(* Logix 5000 project; controller CIP_Sync_Demo_AKD2G_Dual_Axes_v_2_1 vendor 1 type 14 code 156 rev 34.11; software revision 34.01; part 3 of 4 *)
(* tags used below, declared in another part *)
   StateMachineCurrentState : INT;
   UpdatePeriod : DINT;
   Unwind : DINT;
   AxisControlWord : INT;
   AxisVoltageEnabled : BOOL;
   AxisSwitchOnDisabled : BOOL;
   AxisRemote : BOOL;
   AxisHomeAttained : BOOL;
   AxisHomingError : BOOL;
   AxisMotionModeHoming : BOOL;
   AxisMotionModeCyclicPosition : BOOL;
   AxisFollowingError : BOOL;
   AxisStreamingActive : BOOL;
   UpdatePeriodMsgSent : BOOL;
   UnwindMsgSent : BOOL;
   IsRotary : SINT;
(* CIP_Axis_State_Machine, continued *)

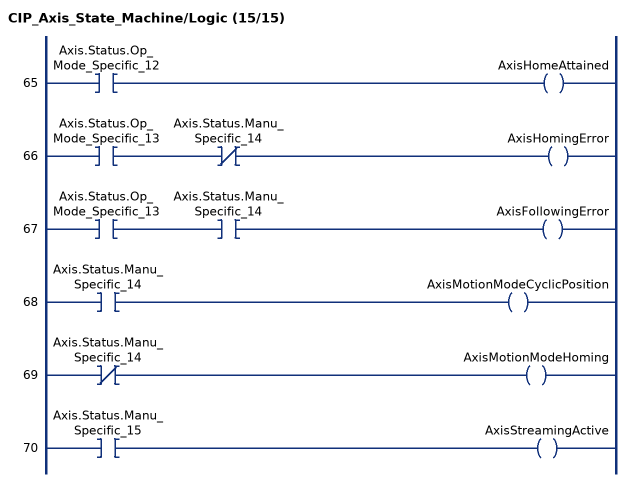
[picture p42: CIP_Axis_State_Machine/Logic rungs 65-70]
   65: XIC(Axis.Status.Op_Mode_Specific_12)OTE(AxisHomeAttained);
   66: XIC(Axis.Status.Op_Mode_Specific_13)XIO(Axis.Status.Manu_Specific_14)OTE(AxisHomingError);
   67: XIC(Axis.Status.Op_Mode_Specific_13)XIC(Axis.Status.Manu_Specific_14)OTE(AxisFollowingError);
   68: XIC(Axis.Status.Manu_Specific_14)OTE(AxisMotionModeCyclicPosition);
   69: XIO(Axis.Status.Manu_Specific_14)OTE(AxisMotionModeHoming);
   70: XIC(Axis.Status.Manu_Specific_15)OTE(AxisStreamingActive);
END_ROUTINE

ROUTINE Prescan   (* ladder *)
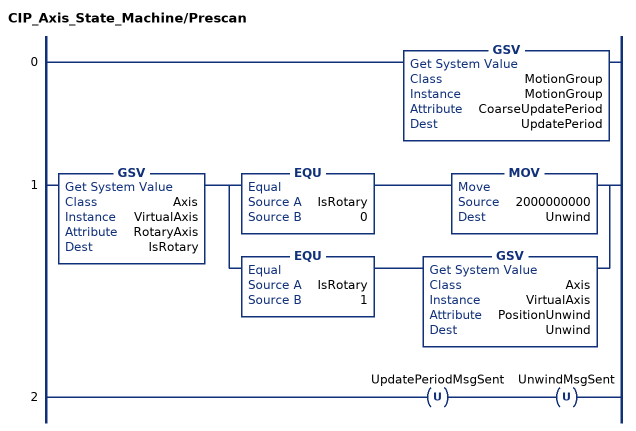
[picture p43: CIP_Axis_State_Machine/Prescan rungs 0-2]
   0: GSV(MotionGroup,MotionGroup,CoarseUpdatePeriod,UpdatePeriod);
   1: GSV(Axis,VirtualAxis,RotaryAxis,IsRotary)[EQU(IsRotary,0) MOV(2000000000,Unwind) ,EQU(IsRotary,1) GSV(Axis,VirtualAxis,PositionUnwind,Unwind) ];
   2: OTU(UpdatePeriodMsgSent)OTU(UnwindMsgSent);
END_ROUTINE
END_ADD_ON_INSTRUCTION

ADD_ON_INSTRUCTION CIP_Drive_Comms_Dual_Axis   (* revision 2.1, ExecutePrescan *)
// CIP Sync Drive Communications For AKD2G Dual Axis Drive
// Revision note:
// Changed local tag CycleStartTime from LINT to DINT[2]. Changed GSV destination and both COP instruction Source entries to use CycleStartTime[0] as a result of the change in data typing.
VAR_IN_OUT
   InputFromDrive : SINT[64]; {required}
   OutputToDrive : SINT[64]; {required}
   Axis1 : CIP_Axis; {required}
   Axis2 : CIP_Axis; {required}
   VirtualAxis1 : AXIS_VIRTUAL; {required}
   VirtualAxis2 : AXIS_VIRTUAL; {required}
   MotionGroup : MOTION_GROUP; {required}
   DynamicMap : CIP_DynamicMap; {required}
END_VAR
VAR
   CycleStartTime : DINT[2]; {access None}
   AxisPosition : DINT; {access None}
END_VAR

ROUTINE Logic   (* ladder *)
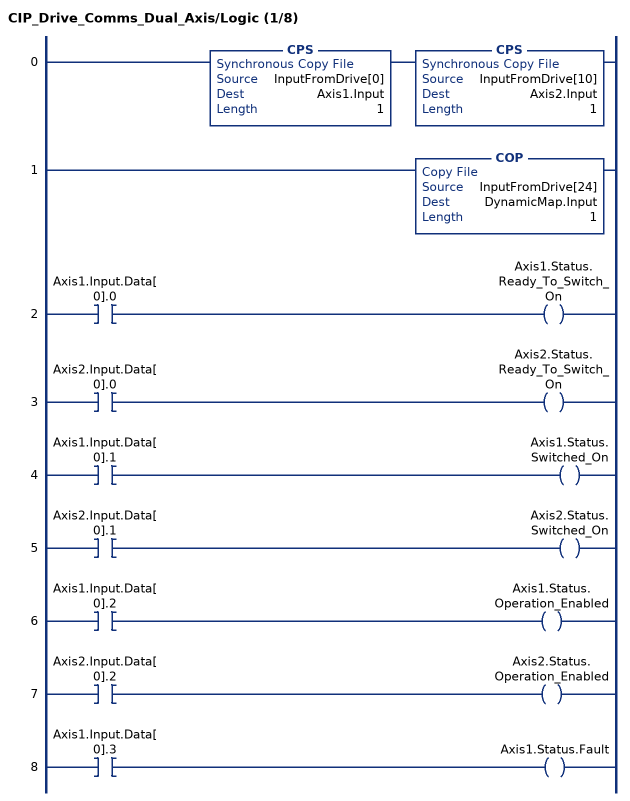
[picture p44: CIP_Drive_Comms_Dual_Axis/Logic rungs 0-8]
   0: CPS(InputFromDrive[0],Axis1.Input,1)CPS(InputFromDrive[10],Axis2.Input,1);
   1: COP(InputFromDrive[24],DynamicMap.Input,1);
   2: XIC(Axis1.Input.Data[0].0)OTE(Axis1.Status.Ready_To_Switch_On);
   3: XIC(Axis2.Input.Data[0].0)OTE(Axis2.Status.Ready_To_Switch_On);
   4: XIC(Axis1.Input.Data[0].1)OTE(Axis1.Status.Switched_On);
   5: XIC(Axis2.Input.Data[0].1)OTE(Axis2.Status.Switched_On);
   6: XIC(Axis1.Input.Data[0].2)OTE(Axis1.Status.Operation_Enabled);
   7: XIC(Axis2.Input.Data[0].2)OTE(Axis2.Status.Operation_Enabled);
   8: XIC(Axis1.Input.Data[0].3)OTE(Axis1.Status.Fault);
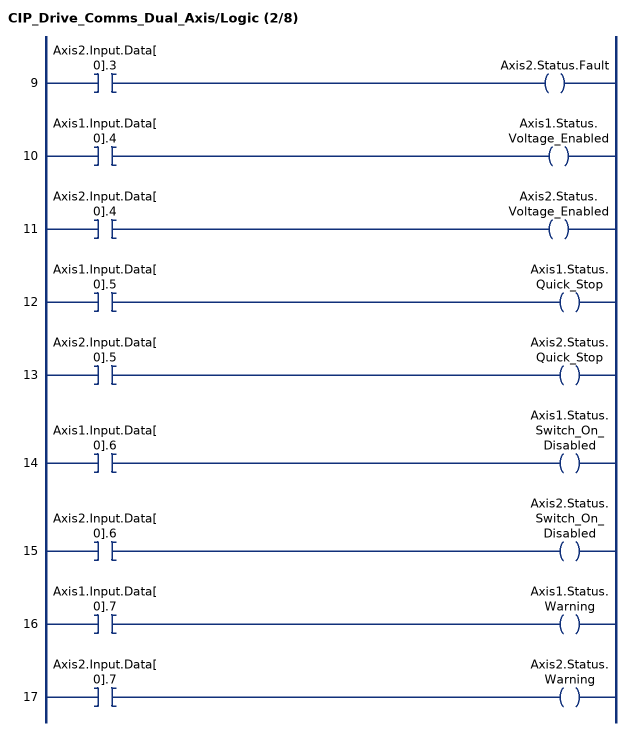
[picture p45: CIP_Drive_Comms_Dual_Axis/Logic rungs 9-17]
   9: XIC(Axis2.Input.Data[0].3)OTE(Axis2.Status.Fault);
   10: XIC(Axis1.Input.Data[0].4)OTE(Axis1.Status.Voltage_Enabled);
   11: XIC(Axis2.Input.Data[0].4)OTE(Axis2.Status.Voltage_Enabled);
   12: XIC(Axis1.Input.Data[0].5)OTE(Axis1.Status.Quick_Stop);
   13: XIC(Axis2.Input.Data[0].5)OTE(Axis2.Status.Quick_Stop);
   14: XIC(Axis1.Input.Data[0].6)OTE(Axis1.Status.Switch_On_Disabled);
   15: XIC(Axis2.Input.Data[0].6)OTE(Axis2.Status.Switch_On_Disabled);
   16: XIC(Axis1.Input.Data[0].7)OTE(Axis1.Status.Warning);
   17: XIC(Axis2.Input.Data[0].7)OTE(Axis2.Status.Warning);
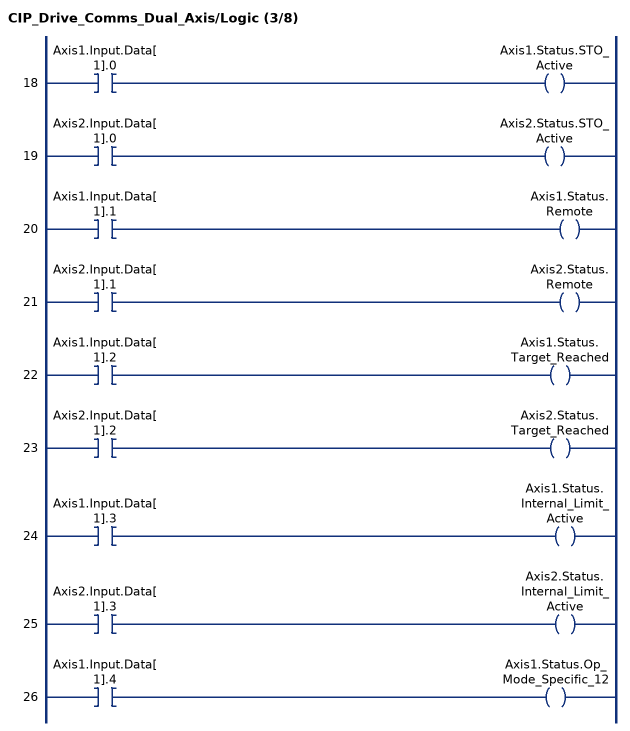
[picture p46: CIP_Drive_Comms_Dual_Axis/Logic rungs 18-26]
   18: XIC(Axis1.Input.Data[1].0)OTE(Axis1.Status.STO_Active);
   19: XIC(Axis2.Input.Data[1].0)OTE(Axis2.Status.STO_Active);
   20: XIC(Axis1.Input.Data[1].1)OTE(Axis1.Status.Remote);
   21: XIC(Axis2.Input.Data[1].1)OTE(Axis2.Status.Remote);
   22: XIC(Axis1.Input.Data[1].2)OTE(Axis1.Status.Target_Reached);
   23: XIC(Axis2.Input.Data[1].2)OTE(Axis2.Status.Target_Reached);
   24: XIC(Axis1.Input.Data[1].3)OTE(Axis1.Status.Internal_Limit_Active);
   25: XIC(Axis2.Input.Data[1].3)OTE(Axis2.Status.Internal_Limit_Active);
   26: XIC(Axis1.Input.Data[1].4)OTE(Axis1.Status.Op_Mode_Specific_12);
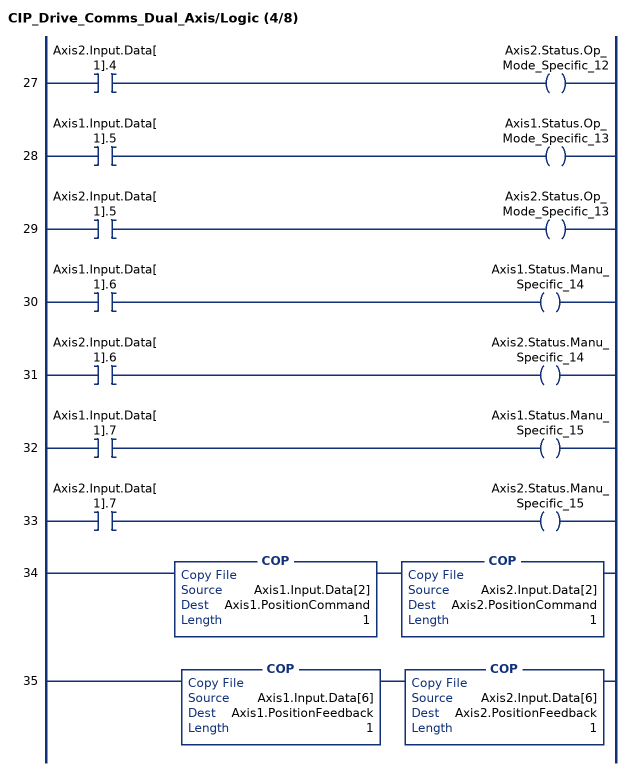
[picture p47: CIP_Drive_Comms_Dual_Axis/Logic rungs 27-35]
   27: XIC(Axis2.Input.Data[1].4)OTE(Axis2.Status.Op_Mode_Specific_12);
   28: XIC(Axis1.Input.Data[1].5)OTE(Axis1.Status.Op_Mode_Specific_13);
   29: XIC(Axis2.Input.Data[1].5)OTE(Axis2.Status.Op_Mode_Specific_13);
   30: XIC(Axis1.Input.Data[1].6)OTE(Axis1.Status.Manu_Specific_14);
   31: XIC(Axis2.Input.Data[1].6)OTE(Axis2.Status.Manu_Specific_14);
   32: XIC(Axis1.Input.Data[1].7)OTE(Axis1.Status.Manu_Specific_15);
   33: XIC(Axis2.Input.Data[1].7)OTE(Axis2.Status.Manu_Specific_15);
   34: COP(Axis1.Input.Data[2],Axis1.PositionCommand,1)COP(Axis2.Input.Data[2],Axis2.PositionCommand,1);
   35: COP(Axis1.Input.Data[6],Axis1.PositionFeedback,1)COP(Axis2.Input.Data[6],Axis2.PositionFeedback,1);
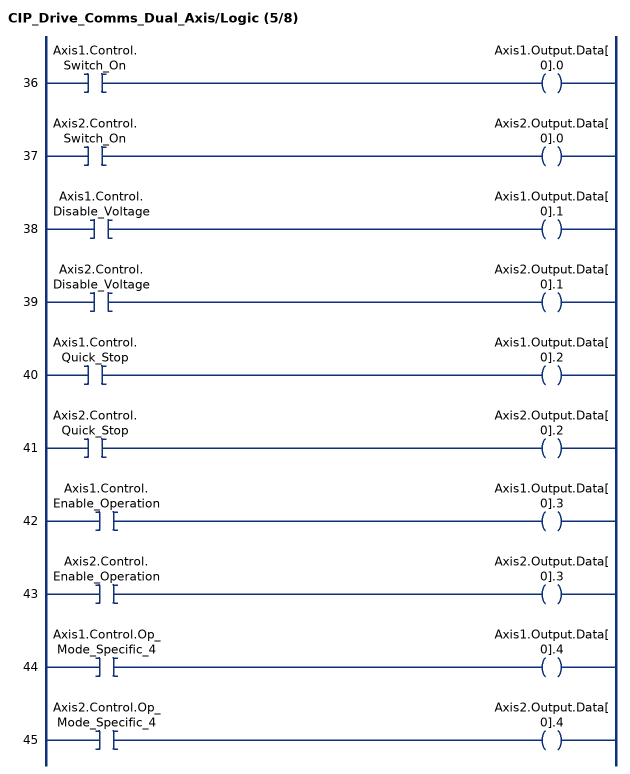
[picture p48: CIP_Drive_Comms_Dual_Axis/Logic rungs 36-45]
   36: XIC(Axis1.Control.Switch_On)OTE(Axis1.Output.Data[0].0);
   37: XIC(Axis2.Control.Switch_On)OTE(Axis2.Output.Data[0].0);
   38: XIC(Axis1.Control.Disable_Voltage)OTE(Axis1.Output.Data[0].1);
   39: XIC(Axis2.Control.Disable_Voltage)OTE(Axis2.Output.Data[0].1);
   40: XIC(Axis1.Control.Quick_Stop)OTE(Axis1.Output.Data[0].2);
   41: XIC(Axis2.Control.Quick_Stop)OTE(Axis2.Output.Data[0].2);
   42: XIC(Axis1.Control.Enable_Operation)OTE(Axis1.Output.Data[0].3);
   43: XIC(Axis2.Control.Enable_Operation)OTE(Axis2.Output.Data[0].3);
   44: XIC(Axis1.Control.Op_Mode_Specific_4)OTE(Axis1.Output.Data[0].4);
   45: XIC(Axis2.Control.Op_Mode_Specific_4)OTE(Axis2.Output.Data[0].4);
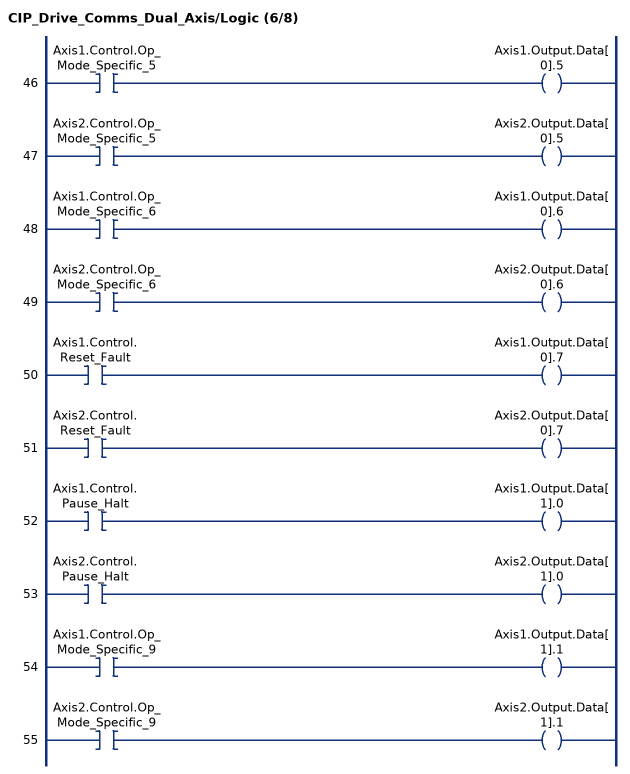
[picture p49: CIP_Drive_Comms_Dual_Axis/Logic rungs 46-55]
   46: XIC(Axis1.Control.Op_Mode_Specific_5)OTE(Axis1.Output.Data[0].5);
   47: XIC(Axis2.Control.Op_Mode_Specific_5)OTE(Axis2.Output.Data[0].5);
   48: XIC(Axis1.Control.Op_Mode_Specific_6)OTE(Axis1.Output.Data[0].6);
   49: XIC(Axis2.Control.Op_Mode_Specific_6)OTE(Axis2.Output.Data[0].6);
   50: XIC(Axis1.Control.Reset_Fault)OTE(Axis1.Output.Data[0].7);
   51: XIC(Axis2.Control.Reset_Fault)OTE(Axis2.Output.Data[0].7);
   52: XIC(Axis1.Control.Pause_Halt)OTE(Axis1.Output.Data[1].0);
   53: XIC(Axis2.Control.Pause_Halt)OTE(Axis2.Output.Data[1].0);
   54: XIC(Axis1.Control.Op_Mode_Specific_9)OTE(Axis1.Output.Data[1].1);
   55: XIC(Axis2.Control.Op_Mode_Specific_9)OTE(Axis2.Output.Data[1].1);
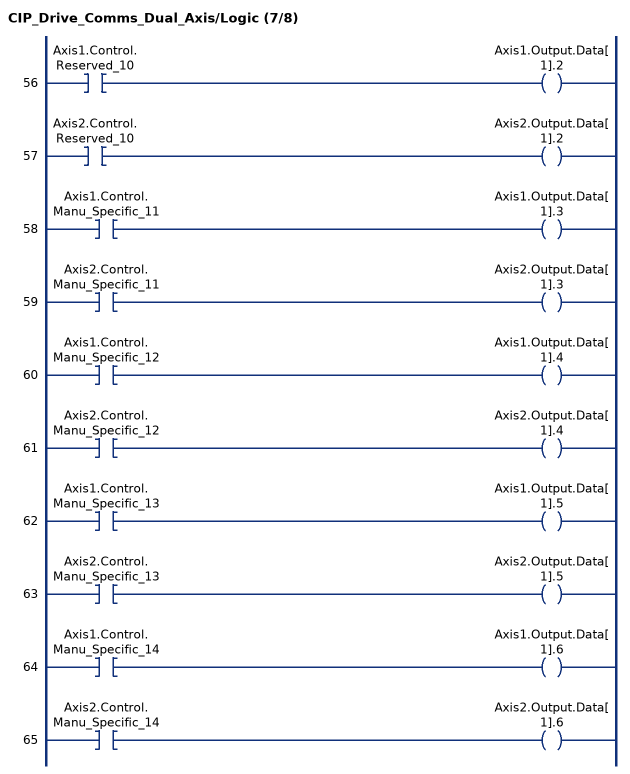
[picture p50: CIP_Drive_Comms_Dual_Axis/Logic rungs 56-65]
   56: XIC(Axis1.Control.Reserved_10)OTE(Axis1.Output.Data[1].2);
   57: XIC(Axis2.Control.Reserved_10)OTE(Axis2.Output.Data[1].2);
   58: XIC(Axis1.Control.Manu_Specific_11)OTE(Axis1.Output.Data[1].3);
   59: XIC(Axis2.Control.Manu_Specific_11)OTE(Axis2.Output.Data[1].3);
   60: XIC(Axis1.Control.Manu_Specific_12)OTE(Axis1.Output.Data[1].4);
   61: XIC(Axis2.Control.Manu_Specific_12)OTE(Axis2.Output.Data[1].4);
   62: XIC(Axis1.Control.Manu_Specific_13)OTE(Axis1.Output.Data[1].5);
   63: XIC(Axis2.Control.Manu_Specific_13)OTE(Axis2.Output.Data[1].5);
   64: XIC(Axis1.Control.Manu_Specific_14)OTE(Axis1.Output.Data[1].6);
   65: XIC(Axis2.Control.Manu_Specific_14)OTE(Axis2.Output.Data[1].6);
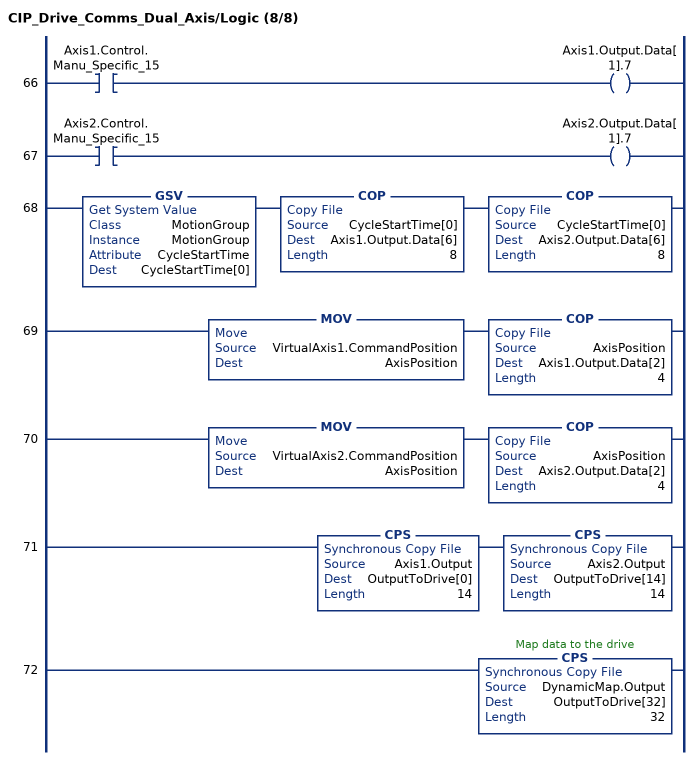
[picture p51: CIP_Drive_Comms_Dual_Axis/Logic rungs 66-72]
   66: XIC(Axis1.Control.Manu_Specific_15)OTE(Axis1.Output.Data[1].7);
   67: XIC(Axis2.Control.Manu_Specific_15)OTE(Axis2.Output.Data[1].7);
   68: GSV(MotionGroup,MotionGroup,CycleStartTime,CycleStartTime[0])COP(CycleStartTime[0],Axis1.Output.Data[6],8)COP(CycleStartTime[0],Axis2.Output.Data[6],8);
   69: MOV(VirtualAxis1.CommandPosition,AxisPosition)COP(AxisPosition,Axis1.Output.Data[2],4);
   70: MOV(VirtualAxis2.CommandPosition,AxisPosition)COP(AxisPosition,Axis2.Output.Data[2],4);
   71: CPS(Axis1.Output,OutputToDrive[0],14)CPS(Axis2.Output,OutputToDrive[14],14);
   72: CPS(DynamicMap.Output,OutputToDrive[32],32);
END_ROUTINE

ROUTINE Prescan   (* ladder *)
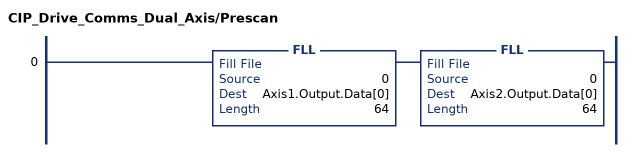
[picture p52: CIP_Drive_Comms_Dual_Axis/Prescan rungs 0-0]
   0: FLL(0,Axis1.Output.Data[0],64)FLL(0,Axis2.Output.Data[0],64);
END_ROUTINE
END_ADD_ON_INSTRUCTION

ADD_ON_INSTRUCTION CIP_Drive_Comms_Single_Axis   (* revision 2.1, ExecutePrescan *)
// CIP Sync Drive Communications For AKD2G Single Axis or Essentials Drive
// Revision note:
// Changed Local Tag CycleStartTime from LINT to DINT[2]
// Modified GSV Destination and COP Source to CycleStartTime[0] in rung 36 to accommodate the change in data typing.
VAR_IN_OUT
   InputFromDrive : SINT[64]; {required}
   OutputToDrive : SINT[64]; {required}
   Axis : CIP_Axis; {required}
   VirtualAxis : AXIS_VIRTUAL; {required}
   MotionGroup : MOTION_GROUP; {required}
   DynamicMap : CIP_DynamicMap; {required}
END_VAR
VAR
   CycleStartTime : DINT[2]; {access None}
   AxisPosition : DINT; {access None}
END_VAR

ROUTINE Logic   (* ladder *)
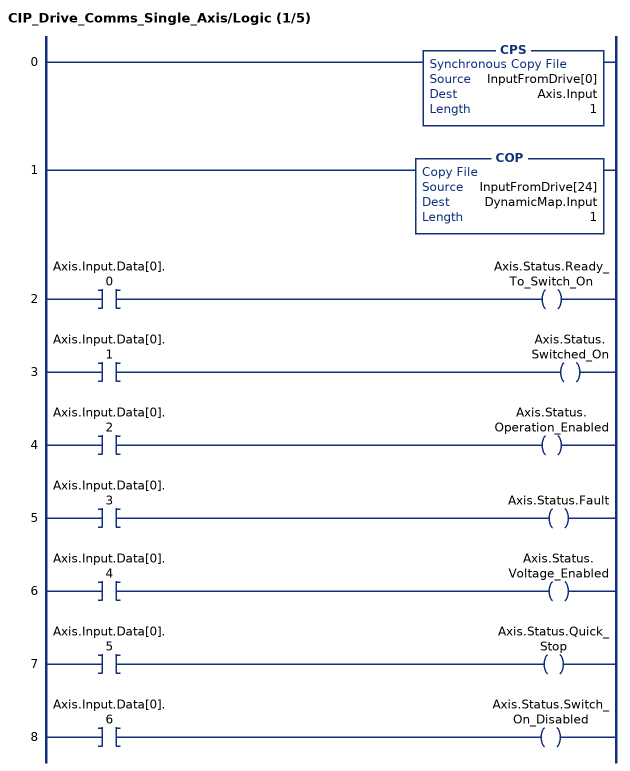
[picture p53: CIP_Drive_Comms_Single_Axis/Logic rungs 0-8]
   0: CPS(InputFromDrive[0],Axis.Input,1);
   1: COP(InputFromDrive[24],DynamicMap.Input,1);
   2: XIC(Axis.Input.Data[0].0)OTE(Axis.Status.Ready_To_Switch_On);
   3: XIC(Axis.Input.Data[0].1)OTE(Axis.Status.Switched_On);
   4: XIC(Axis.Input.Data[0].2)OTE(Axis.Status.Operation_Enabled);
   5: XIC(Axis.Input.Data[0].3)OTE(Axis.Status.Fault);
   6: XIC(Axis.Input.Data[0].4)OTE(Axis.Status.Voltage_Enabled);
   7: XIC(Axis.Input.Data[0].5)OTE(Axis.Status.Quick_Stop);
   8: XIC(Axis.Input.Data[0].6)OTE(Axis.Status.Switch_On_Disabled);
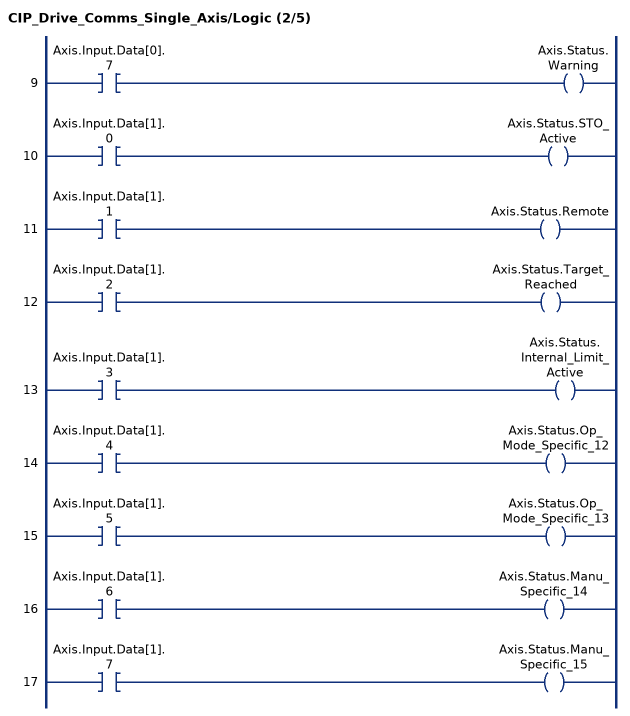
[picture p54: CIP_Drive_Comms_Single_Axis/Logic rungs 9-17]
   9: XIC(Axis.Input.Data[0].7)OTE(Axis.Status.Warning);
   10: XIC(Axis.Input.Data[1].0)OTE(Axis.Status.STO_Active);
   11: XIC(Axis.Input.Data[1].1)OTE(Axis.Status.Remote);
   12: XIC(Axis.Input.Data[1].2)OTE(Axis.Status.Target_Reached);
   13: XIC(Axis.Input.Data[1].3)OTE(Axis.Status.Internal_Limit_Active);
   14: XIC(Axis.Input.Data[1].4)OTE(Axis.Status.Op_Mode_Specific_12);
   15: XIC(Axis.Input.Data[1].5)OTE(Axis.Status.Op_Mode_Specific_13);
   16: XIC(Axis.Input.Data[1].6)OTE(Axis.Status.Manu_Specific_14);
   17: XIC(Axis.Input.Data[1].7)OTE(Axis.Status.Manu_Specific_15);
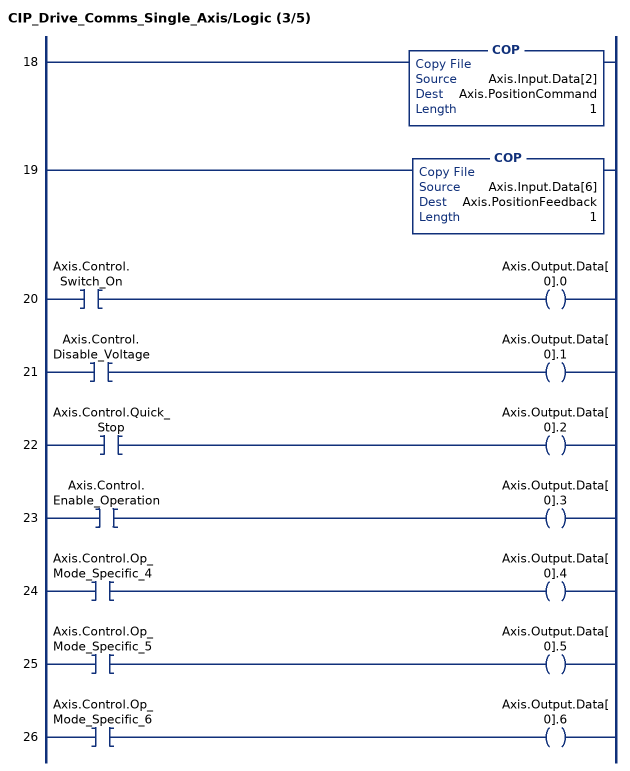
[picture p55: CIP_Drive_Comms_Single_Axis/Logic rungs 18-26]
   18: COP(Axis.Input.Data[2],Axis.PositionCommand,1);
   19: COP(Axis.Input.Data[6],Axis.PositionFeedback,1);
   20: XIC(Axis.Control.Switch_On)OTE(Axis.Output.Data[0].0);
   21: XIC(Axis.Control.Disable_Voltage)OTE(Axis.Output.Data[0].1);
   22: XIC(Axis.Control.Quick_Stop)OTE(Axis.Output.Data[0].2);
   23: XIC(Axis.Control.Enable_Operation)OTE(Axis.Output.Data[0].3);
   24: XIC(Axis.Control.Op_Mode_Specific_4)OTE(Axis.Output.Data[0].4);
   25: XIC(Axis.Control.Op_Mode_Specific_5)OTE(Axis.Output.Data[0].5);
   26: XIC(Axis.Control.Op_Mode_Specific_6)OTE(Axis.Output.Data[0].6);
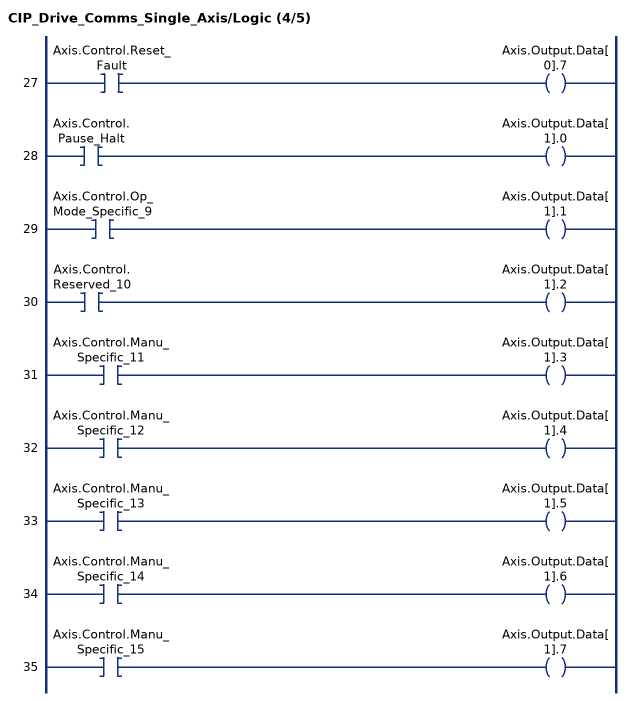
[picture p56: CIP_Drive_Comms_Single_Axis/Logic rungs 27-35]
   27: XIC(Axis.Control.Reset_Fault)OTE(Axis.Output.Data[0].7);
   28: XIC(Axis.Control.Pause_Halt)OTE(Axis.Output.Data[1].0);
   29: XIC(Axis.Control.Op_Mode_Specific_9)OTE(Axis.Output.Data[1].1);
   30: XIC(Axis.Control.Reserved_10)OTE(Axis.Output.Data[1].2);
   31: XIC(Axis.Control.Manu_Specific_11)OTE(Axis.Output.Data[1].3);
   32: XIC(Axis.Control.Manu_Specific_12)OTE(Axis.Output.Data[1].4);
   33: XIC(Axis.Control.Manu_Specific_13)OTE(Axis.Output.Data[1].5);
   34: XIC(Axis.Control.Manu_Specific_14)OTE(Axis.Output.Data[1].6);
   35: XIC(Axis.Control.Manu_Specific_15)OTE(Axis.Output.Data[1].7);
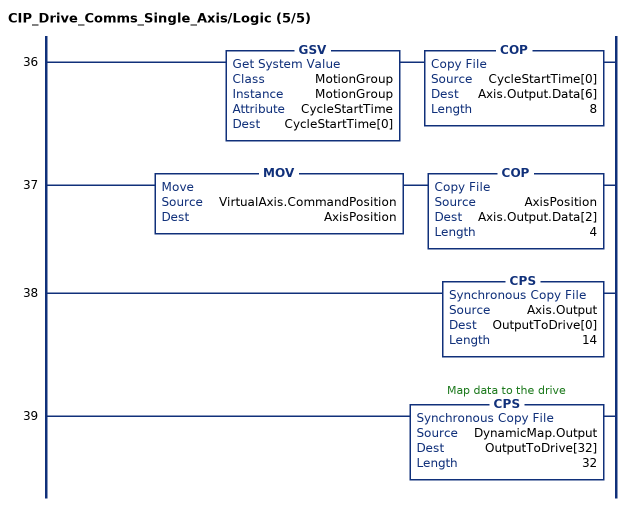
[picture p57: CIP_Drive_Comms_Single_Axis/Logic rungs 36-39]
   36: GSV(MotionGroup,MotionGroup,CycleStartTime,CycleStartTime[0])COP(CycleStartTime[0],Axis.Output.Data[6],8);
   37: MOV(VirtualAxis.CommandPosition,AxisPosition)COP(AxisPosition,Axis.Output.Data[2],4);
   38: CPS(Axis.Output,OutputToDrive[0],14);
   39: CPS(DynamicMap.Output,OutputToDrive[32],32);
END_ROUTINE

ROUTINE Prescan   (* ladder *)
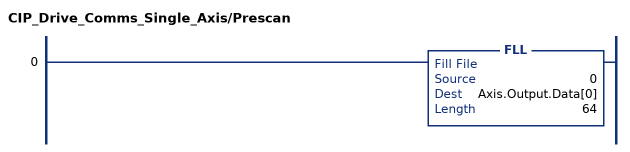
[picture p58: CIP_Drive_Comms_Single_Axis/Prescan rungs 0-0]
   0: FLL(0,Axis.Output.Data[0],64);
END_ROUTINE
END_ADD_ON_INSTRUCTION

VAR_GLOBAL   (* controller tags *)
   AKD2G : CIP_Drive_Comms_Dual_Axis;
   ax1_Cip_State_Machine : CIP_Axis_State_Machine := (StateMachineCurrentState := 1, UpdatePeriod := 2000, Unwind := 360000, AxisVoltageEnabled := 1, AxisSwitchOnDisabled := 1, AxisRemote := 1, AxisHomeAttained := 1, AxisMotionModeCyclicPosition := 1);
   Ax1_Current_State : STRING := 'Switch On Disabled';
   Ax1_Cyclic_Pos_Dis_AOI : CIP_Axis_Disable_Streaming;
   Ax1_Cyclic_Pos_Dis_Err_Description : STRING := 'No Error';
   Ax1_Cyclic_Pos_En_AOI : CIP_Axis_Enable_Streaming;
   Ax1_Cyclic_Pos_En_Err_Description : STRING := 'No Error';
   ax1_cyclic_position_off_request : BOOL;
   ax1_cyclic_position_on_request : BOOL;
   Ax1_Disable_AOI : CIP_Axis_Disable;
   Ax1_Disable_Error_Description : STRING := 'No Error';
   Ax1_Disable_Request_OS : BOOL;
   ax1_disable_streaming_os : BOOL;
   Ax1_Disable_Toggle : BOOL;
   Ax1_Enable_AOI : CIP_Axis_Enable;
   Ax1_Enable_Error_Description : STRING := 'No Error';
   Ax1_Enable_Request_OS : BOOL;
   ax1_enable_streaming_os : BOOL;
   Ax1_Enable_Toggle : BOOL;
   Ax1_Error_Message : STRING := 'No Error';
   Ax1_Extend : BOOL;
   ax1_extend_abs_move : MOTION_INSTRUCTION := (FLAGS := 33554432);
   Ax1_Extend_Target_Pos : DINT;
   Ax1_Fault_Reset_AOI : CIP_Axis_Fault_Reset;
   Ax1_Fault_Reset_Error_Description : STRING := 'No Error';
   Ax1_FAULT_RESET_OS : BOOL;
   Ax1_Fault_Reset_Toggle : BOOL;
   Ax1_Home : BOOL;
   Ax1_Home_AOI : CIP_Axis_Home := (TimeOut_mS := 25000);
   Ax1_Home_Error_Description : STRING := 'No Error';
   Ax1_Homed : BOOL := 1;
   Ax1_Jog_Fwd : BOOL;
   Ax1_Jog_Rev : BOOL;
   AX1_MAJ1 : MOTION_INSTRUCTION := (FLAGS := 33554432);
   AX1_MAJ2 : MOTION_INSTRUCTION := (FLAGS := 33554432);
   Ax1_MAS1 : MOTION_INSTRUCTION := (FLAGS := 33554432);
   Ax1_Position_Cmd_Rsp_Assy : DINT := 232081;
   Ax1_Position_Fbk_Rsp_Assy : DINT := 232078;
   Ax1_Quick_Stop_Active : BOOL;
   Ax1_Quick_Stop_AOI : CIP_Axis_Quick_Stop := (TimeOut_mS := 20000);
   Ax1_Quick_Stop_Error_Description : STRING := 'No Error';
   Ax1_Quick_Stop_MSG : MESSAGE;
        MessageParameters(ServiceCode := 16#000e, DestinationTag := Ax1_Quick_Stop_AOI.Quick_Stop_Option_Code_Read, ...)
   Ax1_Quick_Stop_OS : BOOL;
   Ax1_Quick_Stop_Toggle : BOOL;
   Ax1_Retract : BOOL;
   ax1_retract_abs_move : MOTION_INSTRUCTION := (FLAGS := 33554432);
   ax1_start_home_ons : BOOL;
   Ax1_Stop_Cmd : BOOL;   // Axis Stop Command under normal streaming conditions
   Ax1_Stop_Cmd2 : BOOL;   // Axis Stop Command in the event the axis is disabled (disable or quick stop option code is 1 or 2 ) or disabled by fault
   Ax1_Stop_Cmd3 : BOOL;   // Axis Stop Command if streaming is disabled
   Ax1_Stop_OS : BOOL := 1;
   Ax1_Stop_OS2 : BOOL := 1;
   Ax1_Stop_OS3 : BOOL;
   Ax1_Streaming_Active : BOOL;
   Ax1_UnwindMsg : MESSAGE;
        MessageParameters(ServiceCode := 16#0010, LocalElement := ax1_Cip_State_Machine.Unwind, ...)
   Ax1_UpdatePeriodMsg : MESSAGE;
        MessageParameters(ServiceCode := 16#0010, LocalElement := ax1_Cip_State_Machine.UpdatePeriod, ...)
   Ax1_Virtual_Master_Actual_Position : DINT := 232081;
   Ax1_Virtual_Master_Cmd_Pos : DINT := 232081;
   ax2_Cip_State_Machine : CIP_Axis_State_Machine := (StateMachineCurrentState := 1, UpdatePeriod := 2000, Unwind := 2000000000, AxisControlWord := 2#0000_0000_0000_1001, AxisVoltageEnabled := 1, AxisSwitchOnDisabled := 1, AxisRemote := 1, AxisHomeAttained := 1, AxisMotionModeCyclicPosition := 1);
   Ax2_Current_State : STRING := 'Switch On Disabled';
   Ax2_Cyclic_Pos_Dis_AOI : CIP_Axis_Disable_Streaming;
   Ax2_Cyclic_Pos_Dis_Err_Description : STRING := 'No Error';
   Ax2_Cyclic_Pos_En_AOI : CIP_Axis_Enable_Streaming;
   Ax2_Cyclic_Pos_En_Err_Description : STRING := 'No Error';
   ax2_cyclic_position_off_request : BOOL;
   ax2_cyclic_position_on_request : BOOL;
   Ax2_Disable_AOI : CIP_Axis_Disable;
   Ax2_Disable_Error_Description : STRING := 'No Error';
   Ax2_Disable_Request_OS : BOOL;
   ax2_disable_streaming_os : BOOL;
   Ax2_Enable_AOI : CIP_Axis_Enable;
   Ax2_Enable_Error_Description : STRING := 'No Error';
   Ax2_Enable_Request_OS : BOOL;
   ax2_enable_streaming_os : BOOL;
   Ax2_Enable_Toggle : BOOL;
   Ax2_Error_Message : STRING := 'No Error';
   Ax2_Extend : BOOL;
   ax2_extend_abs_move : MOTION_INSTRUCTION := (FLAGS := 33554432);
   Ax2_Extend_Target_Pos : DINT;
   Ax2_Fault_Reset_AOI : CIP_Axis_Fault_Reset;
   Ax2_Fault_Reset_Error_Description : STRING := 'No Error';
   Ax2_FAULT_RESET_OS : BOOL;
   AX2_Fault_Reset_Toggle : BOOL;
   ax2_home : BOOL;
   Ax2_Home_AOI : CIP_Axis_Home := (TimeOut_mS := 5000);
   Ax2_Home_Error_Description : STRING := 'No Error';
   Ax2_Homed : BOOL := 1;
   Ax2_Jog_Fwd : BOOL;
   Ax2_Jog_Rev : BOOL;
   AX2_MAJ1 : MOTION_INSTRUCTION := (FLAGS := 33554432);
   AX2_MAJ2 : MOTION_INSTRUCTION := (FLAGS := 33554432);
   Ax2_MAS1 : MOTION_INSTRUCTION := (FLAGS := 33554432);
   Ax2_Position_Cmd_Rsp_Assy : DINT := 49978;
   Ax2_Position_Fbk_Rsp_Assy : DINT := 49978;
   Ax2_Quick_Stop_Active : BOOL;
   Ax2_Quick_Stop_AOI : CIP_Axis_Quick_Stop := (TimeOut_mS := 25000);
   Ax2_Quick_Stop_Error_Description : STRING := 'No Error';
   Ax2_Quick_Stop_In_Progress : BOOL;
   Ax2_Quick_Stop_MSG : MESSAGE;
        MessageParameters(ServiceCode := 16#000e, DestinationTag := Ax2_Quick_Stop_AOI.Quick_Stop_Option_Code_Read, ...)
   Ax2_Quick_Stop_OS : BOOL;
   Ax2_Quick_Stop_Toggle : BOOL;
   Ax2_Retract : BOOL;
   ax2_retract_abs_move : MOTION_INSTRUCTION := (FLAGS := 33554432);
   ax2_start_home_ons : BOOL;
   Ax2_Stop_Cmd : BOOL;   // Axis Stop Command under normal streaming conditions
   Ax2_Stop_Cmd2 : BOOL;   // Axis Stop Command in the event the axis is disabled (disable or quick stop option code is 1 or 2 ) or disabled by fault
   Ax2_Stop_Cmd3 : BOOL;   // Axis Stop Command if streaming is disabled
   Ax2_Stop_OS : BOOL := 1;
   Ax2_Stop_OS2 : BOOL := 1;
   Ax2_Stop_OS3 : BOOL;
   Ax2_Streaming_Active : BOOL;
   Ax2_UnwindMsg : MESSAGE;
        MessageParameters(ServiceCode := 16#0010, LocalElement := ax2_Cip_State_Machine.Unwind, ...)
   Ax2_UpdatePeriodMsg : MESSAGE;
        MessageParameters(ServiceCode := 16#0010, LocalElement := ax2_Cip_State_Machine.UpdatePeriod, ...)
   Ax2_Virtual_Master_Actual_Position : DINT := 49978;
   Ax2_Virtual_Master_Cmd_Pos : DINT := 49978;
   Axis1_Disabled : BOOL := 1;
   Axis1_Enabled : BOOL;
   Axis1_Faulted : BOOL;
   Axis1_Rotary : AXIS_VIRTUAL;
   Axis2_Disable_Toggle : BOOL;
   Axis2_Disabled : BOOL := 1;
   Axis2_Enabled : BOOL;
   Axis2_Faulted : BOOL;
   Axis2_Linear : AXIS_VIRTUAL;
   AXIS_ONE : CIP_Axis := (Status.Voltage_Enabled := 1, Status.Switch_On_Disabled := 1, Status.Remote := 1, Status.Op_Mode_Specific_12 := 1, Status.Manu_Specific_14 := 1, Input.Data[0] := 80, Input.Data[1] := 82, Input.Data[2] := -111, Input.Data[3] := -118, Input.Data[4] := 3, Input.Data[6] := -115, Input.Data[7] := -118, Input.Data[8] := 3, Output.Data[2] := -111, Output.Data[3] := -118, Output.Data[4] := 3, Output.Data[6] := -16, Output.Data[7] := 91, Output.Data[8] := -88, Output.Data[9] := -61, Output.Data[10] := 24, Output.Data[11] := 69, Output.Data[12] := 3, PositionFeedback := 232077, PositionCommand := 232081);
   AXIS_TWO : CIP_Axis := (Control.Switch_On := 1, Control.Enable_Operation := 1, Status.Voltage_Enabled := 1, Status.Switch_On_Disabled := 1, Status.Remote := 1, Status.Op_Mode_Specific_12 := 1, Status.Manu_Specific_14 := 1, Input.Data[0] := 80, Input.Data[1] := 82, Input.Data[2] := 58, Input.Data[3] := -61, Input.Data[6] := 58, Input.Data[7] := -61, Output.Data[0] := 9, Output.Data[2] := 58, Output.Data[3] := -61, Output.Data[6] := -64, Output.Data[7] := 39, Output.Data[8] := -78, Output.Data[9] := -61, Output.Data[10] := 24, Output.Data[11] := 69, Output.Data[12] := 3, PositionFeedback := 49978, PositionCommand := 49978);
   DynamicMap : CIP_DynamicMap := (Input.Data[0] := -4, Input.Data[1] := -1, Input.Data[2] := -1, Input.Data[3] := -1, Input.Data[4] := -4, Input.Data[5] := -1, Input.Data[6] := -1, Input.Data[7] := -1);
   MotionGroup : MOTION_GROUP;
   portcfg_value : INT[3] := ([0] := 1, [1] := 1, [2] := 1); {constant}
   portconfig_msg : MESSAGE;
        MessageParameters(ServiceCode := 16#0010, LocalElement := portcfg_value, ...)
   ptpenable_msg : MESSAGE;
        MessageParameters(ServiceCode := 16#0010, LocalElement := ptpenable_value, ...)
   ptpenable_value : SINT := 1; {constant}
END_VAR

PROGRAM IOProgram   (* main routine IO_Routine_with_CIP_Drive_Comms *)

ROUTINE IO_Routine_with_CIP_Drive_Comms   (* ladder *)
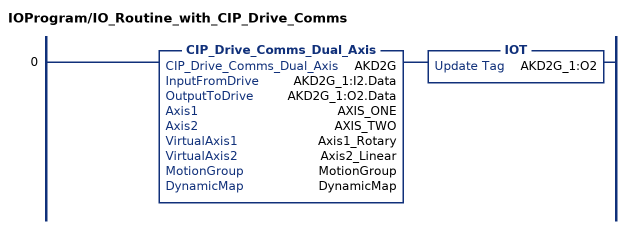
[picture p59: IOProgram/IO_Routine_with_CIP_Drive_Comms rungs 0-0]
   0: CIP_Drive_Comms_Dual_Axis(AKD2G,AKD2G_1:I2.Data,AKD2G_1:O2.Data,AXIS_ONE,AXIS_TWO,Axis1_Rotary,Axis2_Linear,MotionGroup,DynamicMap)IOT(AKD2G_1:O2);
END_ROUTINE
END_PROGRAM
(* Logix 5000 project; controller CIP_Sync_Demo_AKD2G_Dual_Axes_v_2_1 vendor 1 type 14 code 156 rev 34.11; software revision 34.01; part 4 of 4 *)
(* tags used below, declared in another part *)
   AKD2G : CIP_Drive_Comms_Dual_Axis;
   ax1_Cip_State_Machine : CIP_Axis_State_Machine;
   Ax1_Current_State : STRING;
   Ax1_Cyclic_Pos_Dis_AOI : CIP_Axis_Disable_Streaming;
   Ax1_Cyclic_Pos_Dis_Err_Description : STRING;
   Ax1_Cyclic_Pos_En_AOI : CIP_Axis_Enable_Streaming;
   Ax1_Cyclic_Pos_En_Err_Description : STRING;
   ax1_cyclic_position_off_request : BOOL;
   ax1_cyclic_position_on_request : BOOL;
   Ax1_Disable_AOI : CIP_Axis_Disable;
   Ax1_Disable_Error_Description : STRING;
   Ax1_Disable_Request_OS : BOOL;
   ax1_disable_streaming_os : BOOL;
   Ax1_Disable_Toggle : BOOL;
   Ax1_Enable_AOI : CIP_Axis_Enable;
   Ax1_Enable_Error_Description : STRING;
   Ax1_Enable_Request_OS : BOOL;
   ax1_enable_streaming_os : BOOL;
   Ax1_Enable_Toggle : BOOL;
   Ax1_Error_Message : STRING;
   Ax1_Extend : BOOL;
   ax1_extend_abs_move : MOTION_INSTRUCTION;
   Ax1_Extend_Target_Pos : DINT;
   Ax1_Fault_Reset_AOI : CIP_Axis_Fault_Reset;
   Ax1_Fault_Reset_Error_Description : STRING;
   Ax1_FAULT_RESET_OS : BOOL;
   Ax1_Fault_Reset_Toggle : BOOL;
   Ax1_Home : BOOL;
   Ax1_Home_AOI : CIP_Axis_Home;
   Ax1_Home_Error_Description : STRING;
   Ax1_Homed : BOOL;
   Ax1_Jog_Fwd : BOOL;
   Ax1_Jog_Rev : BOOL;
   AX1_MAJ1 : MOTION_INSTRUCTION;
   AX1_MAJ2 : MOTION_INSTRUCTION;
   Ax1_MAS1 : MOTION_INSTRUCTION;
   Ax1_Position_Cmd_Rsp_Assy : DINT;
   Ax1_Position_Fbk_Rsp_Assy : DINT;
   Ax1_Quick_Stop_Active : BOOL;
   Ax1_Quick_Stop_AOI : CIP_Axis_Quick_Stop;
   Ax1_Quick_Stop_Error_Description : STRING;
   Ax1_Quick_Stop_MSG : MESSAGE;
   Ax1_Quick_Stop_OS : BOOL;
   Ax1_Quick_Stop_Toggle : BOOL;
   Ax1_Retract : BOOL;
   ax1_retract_abs_move : MOTION_INSTRUCTION;
   ax1_start_home_ons : BOOL;
   Ax1_Stop_Cmd : BOOL;   // Axis Stop Command under normal streaming conditions
   Ax1_Stop_Cmd2 : BOOL;   // Axis Stop Command in the event the axis is disabled (disable or quick stop option code is 1 or 2 ) or disabled by fault
   Ax1_Stop_Cmd3 : BOOL;   // Axis Stop Command if streaming is disabled
   Ax1_Stop_OS : BOOL;
   Ax1_Stop_OS2 : BOOL;
   Ax1_Stop_OS3 : BOOL;
   Ax1_Streaming_Active : BOOL;
   Ax1_UnwindMsg : MESSAGE;
   Ax1_UpdatePeriodMsg : MESSAGE;
   Ax1_Virtual_Master_Actual_Position : DINT;
   Ax1_Virtual_Master_Cmd_Pos : DINT;
   ax2_Cip_State_Machine : CIP_Axis_State_Machine;
   Ax2_Current_State : STRING;
   Ax2_Cyclic_Pos_Dis_AOI : CIP_Axis_Disable_Streaming;
   Ax2_Cyclic_Pos_Dis_Err_Description : STRING;
   Ax2_Cyclic_Pos_En_AOI : CIP_Axis_Enable_Streaming;
   Ax2_Cyclic_Pos_En_Err_Description : STRING;
   ax2_cyclic_position_off_request : BOOL;
   ax2_cyclic_position_on_request : BOOL;
   Ax2_Disable_AOI : CIP_Axis_Disable;
   Ax2_Disable_Error_Description : STRING;
   Ax2_Disable_Request_OS : BOOL;
   ax2_disable_streaming_os : BOOL;
   Ax2_Enable_AOI : CIP_Axis_Enable;
   Ax2_Enable_Error_Description : STRING;
   Ax2_Enable_Request_OS : BOOL;
   ax2_enable_streaming_os : BOOL;
   Ax2_Enable_Toggle : BOOL;
   Ax2_Error_Message : STRING;
   Ax2_Extend : BOOL;
   ax2_extend_abs_move : MOTION_INSTRUCTION;
   Ax2_Extend_Target_Pos : DINT;
   Ax2_Fault_Reset_AOI : CIP_Axis_Fault_Reset;
   Ax2_Fault_Reset_Error_Description : STRING;
   Ax2_FAULT_RESET_OS : BOOL;
   AX2_Fault_Reset_Toggle : BOOL;
   ax2_home : BOOL;
   Ax2_Home_AOI : CIP_Axis_Home;
   Ax2_Home_Error_Description : STRING;
   Ax2_Homed : BOOL;
   Ax2_Jog_Fwd : BOOL;
   Ax2_Jog_Rev : BOOL;
   AX2_MAJ1 : MOTION_INSTRUCTION;
   AX2_MAJ2 : MOTION_INSTRUCTION;
   Ax2_MAS1 : MOTION_INSTRUCTION;
   Ax2_Position_Cmd_Rsp_Assy : DINT;
   Ax2_Position_Fbk_Rsp_Assy : DINT;
   Ax2_Quick_Stop_Active : BOOL;
   Ax2_Quick_Stop_AOI : CIP_Axis_Quick_Stop;
   Ax2_Quick_Stop_Error_Description : STRING;
   Ax2_Quick_Stop_In_Progress : BOOL;
   Ax2_Quick_Stop_MSG : MESSAGE;
   Ax2_Quick_Stop_OS : BOOL;
   Ax2_Quick_Stop_Toggle : BOOL;
   Ax2_Retract : BOOL;
   ax2_retract_abs_move : MOTION_INSTRUCTION;
   ax2_start_home_ons : BOOL;
   Ax2_Stop_Cmd : BOOL;   // Axis Stop Command under normal streaming conditions
   Ax2_Stop_Cmd2 : BOOL;   // Axis Stop Command in the event the axis is disabled (disable or quick stop option code is 1 or 2 ) or disabled by fault
   Ax2_Stop_Cmd3 : BOOL;   // Axis Stop Command if streaming is disabled
   Ax2_Stop_OS : BOOL;
   Ax2_Stop_OS2 : BOOL;
   Ax2_Stop_OS3 : BOOL;
   Ax2_Streaming_Active : BOOL;
   Ax2_UnwindMsg : MESSAGE;
   Ax2_UpdatePeriodMsg : MESSAGE;
   Ax2_Virtual_Master_Actual_Position : DINT;
   Ax2_Virtual_Master_Cmd_Pos : DINT;
   Axis1_Disabled : BOOL;
   Axis1_Enabled : BOOL;
   Axis1_Faulted : BOOL;
   Axis1_Rotary : AXIS_VIRTUAL;
   Axis2_Disable_Toggle : BOOL;
   Axis2_Disabled : BOOL;
   Axis2_Enabled : BOOL;
   Axis2_Faulted : BOOL;
   Axis2_Linear : AXIS_VIRTUAL;
   AXIS_ONE : CIP_Axis;
   AXIS_TWO : CIP_Axis;
   MotionGroup : MOTION_GROUP;

PROGRAM MainProgram   (* main routine MainRoutine_with_CIP_State_Machines *)

ROUTINE Axis1_Routine   (* ladder *)
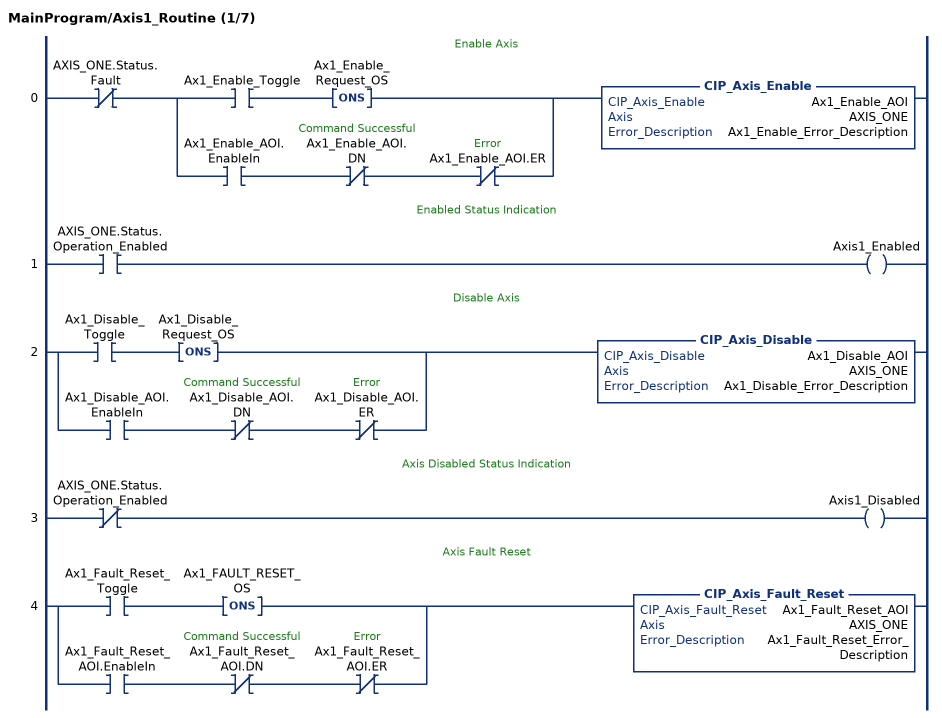
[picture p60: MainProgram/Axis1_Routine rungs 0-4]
   // Enable Axis
   0: XIO(AXIS_ONE.Status.Fault)[XIC(Ax1_Enable_Toggle) ONS(Ax1_Enable_Request_OS) ,XIC(Ax1_Enable_AOI.EnableIn) XIO(Ax1_Enable_AOI.DN) XIO(Ax1_Enable_AOI.ER) ]CIP_Axis_Enable(Ax1_Enable_AOI,AXIS_ONE,Ax1_Enable_Error_Description);
   // Enabled Status Indication
   1: XIC(AXIS_ONE.Status.Operation_Enabled)OTE(Axis1_Enabled);
   // Disable Axis
   2: [XIC(Ax1_Disable_Toggle) ONS(Ax1_Disable_Request_OS) ,XIC(Ax1_Disable_AOI.EnableIn) XIO(Ax1_Disable_AOI.DN) XIO(Ax1_Disable_AOI.ER) ]CIP_Axis_Disable(Ax1_Disable_AOI,AXIS_ONE,Ax1_Disable_Error_Description);
   // Axis Disabled Status Indication
   3: XIO(AXIS_ONE.Status.Operation_Enabled)OTE(Axis1_Disabled);
   // Axis Fault Reset
   4: [XIC(Ax1_Fault_Reset_Toggle) ONS(Ax1_FAULT_RESET_OS) ,XIC(Ax1_Fault_Reset_AOI.EnableIn) XIO(Ax1_Fault_Reset_AOI.DN) XIO(Ax1_Fault_Reset_AOI.ER) ]CIP_Axis_Fault_Reset(Ax1_Fault_Reset_AOI,AXIS_ONE,Ax1_Fault_Reset_Error_Description);
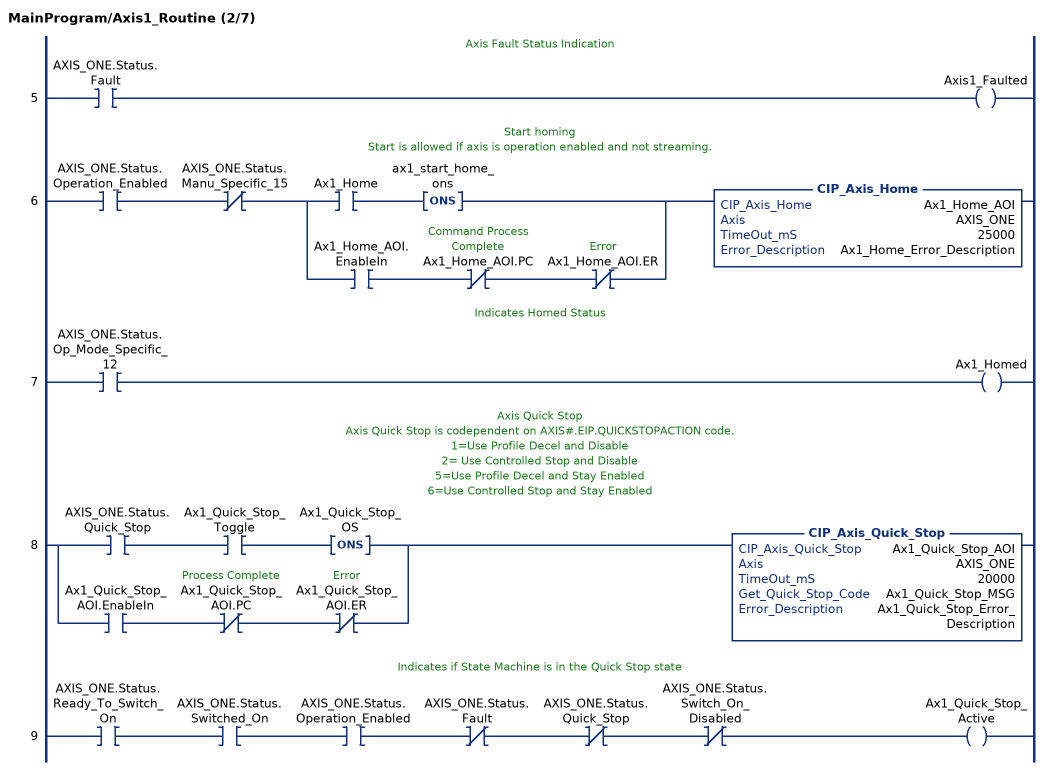
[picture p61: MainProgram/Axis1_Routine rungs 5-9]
   // Axis Fault Status Indication
   5: XIC(AXIS_ONE.Status.Fault)OTE(Axis1_Faulted);
   // Start homing
   // Start is allowed if axis is operation enabled and not streaming.
   6: XIC(AXIS_ONE.Status.Operation_Enabled)XIO(AXIS_ONE.Status.Manu_Specific_15)[XIC(Ax1_Home) ONS(ax1_start_home_ons) ,XIC(Ax1_Home_AOI.EnableIn) XIO(Ax1_Home_AOI.PC) XIO(Ax1_Home_AOI.ER) ]CIP_Axis_Home(Ax1_Home_AOI,AXIS_ONE,25000,Ax1_Home_Error_Description);
   // Indicates Homed Status
   7: XIC(AXIS_ONE.Status.Op_Mode_Specific_12)OTE(Ax1_Homed);
   // Axis Quick Stop
   // Axis Quick Stop is codependent on AXIS#.EIP.QUICKSTOPACTION code.
   // 1=Use Profile Decel and Disable
   // 2= Use Controlled Stop and Disable
   // 5=Use Profile Decel and Stay Enabled
   // 6=Use Controlled Stop and Stay Enabled
   8: [XIC(AXIS_ONE.Status.Quick_Stop) XIC(Ax1_Quick_Stop_Toggle) ONS(Ax1_Quick_Stop_OS) ,XIC(Ax1_Quick_Stop_AOI.EnableIn) XIO(Ax1_Quick_Stop_AOI.PC) XIO(Ax1_Quick_Stop_AOI.ER) ]CIP_Axis_Quick_Stop(Ax1_Quick_Stop_AOI,AXIS_ONE,20000,Ax1_Quick_Stop_MSG,Ax1_Quick_Stop_Error_Description);
   // Indicates if State Machine is in the Quick Stop state
   9: XIC(AXIS_ONE.Status.Ready_To_Switch_On)XIC(AXIS_ONE.Status.Switched_On)XIC(AXIS_ONE.Status.Operation_Enabled)XIO(AXIS_ONE.Status.Fault)XIO(AXIS_ONE.Status.Quick_Stop)XIO(AXIS_ONE.Status.Switch_On_Disabled)OTE(Ax1_Quick_Stop_Active);
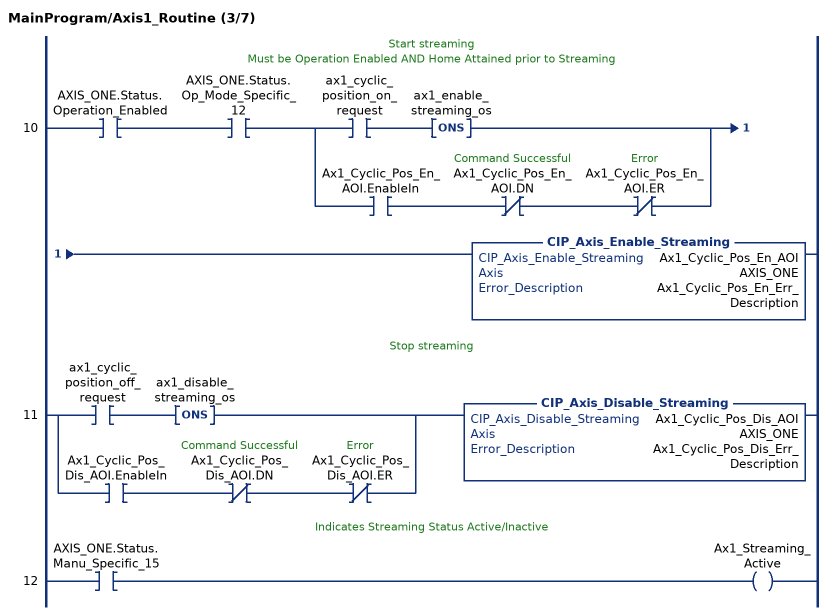
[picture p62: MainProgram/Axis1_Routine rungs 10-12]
   // Start streaming
   // Must be Operation Enabled AND Home Attained prior to Streaming
   10: XIC(AXIS_ONE.Status.Operation_Enabled)XIC(AXIS_ONE.Status.Op_Mode_Specific_12)[XIC(ax1_cyclic_position_on_request) ONS(ax1_enable_streaming_os) ,XIC(Ax1_Cyclic_Pos_En_AOI.EnableIn) XIO(Ax1_Cyclic_Pos_En_AOI.DN) XIO(Ax1_Cyclic_Pos_En_AOI.ER) ]CIP_Axis_Enable_Streaming(Ax1_Cyclic_Pos_En_AOI,AXIS_ONE,Ax1_Cyclic_Pos_En_Err_Description);
   // Stop streaming
   11: [XIC(ax1_cyclic_position_off_request) ONS(ax1_disable_streaming_os) ,XIC(Ax1_Cyclic_Pos_Dis_AOI.EnableIn) XIO(Ax1_Cyclic_Pos_Dis_AOI.DN) XIO(Ax1_Cyclic_Pos_Dis_AOI.ER) ]CIP_Axis_Disable_Streaming(Ax1_Cyclic_Pos_Dis_AOI,AXIS_ONE,Ax1_Cyclic_Pos_Dis_Err_Description);
   // Indicates Streaming Status Active/Inactive
   12: XIC(AXIS_ONE.Status.Manu_Specific_15)OTE(Ax1_Streaming_Active);
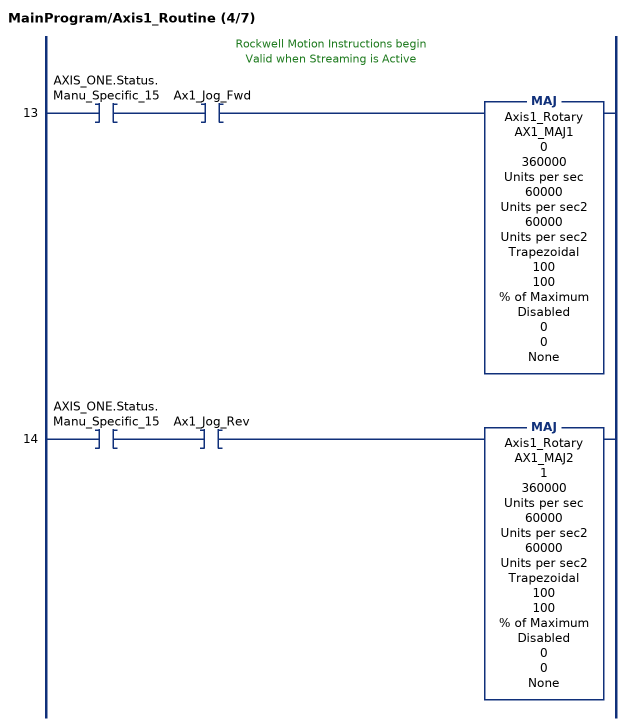
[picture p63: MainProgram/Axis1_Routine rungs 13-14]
   // Rockwell Motion Instructions begin
   // Valid when Streaming is Active
   13: XIC(AXIS_ONE.Status.Manu_Specific_15)XIC(Ax1_Jog_Fwd)MAJ(Axis1_Rotary,AX1_MAJ1,0,360000,Units per sec,60000,Units per sec2,60000,Units per sec2,Trapezoidal,100,100,% of Maximum,Disabled,0,0,None);
   14: XIC(AXIS_ONE.Status.Manu_Specific_15)XIC(Ax1_Jog_Rev)MAJ(Axis1_Rotary,AX1_MAJ2,1,360000,Units per sec,60000,Units per sec2,60000,Units per sec2,Trapezoidal,100,100,% of Maximum,Disabled,0,0,None);
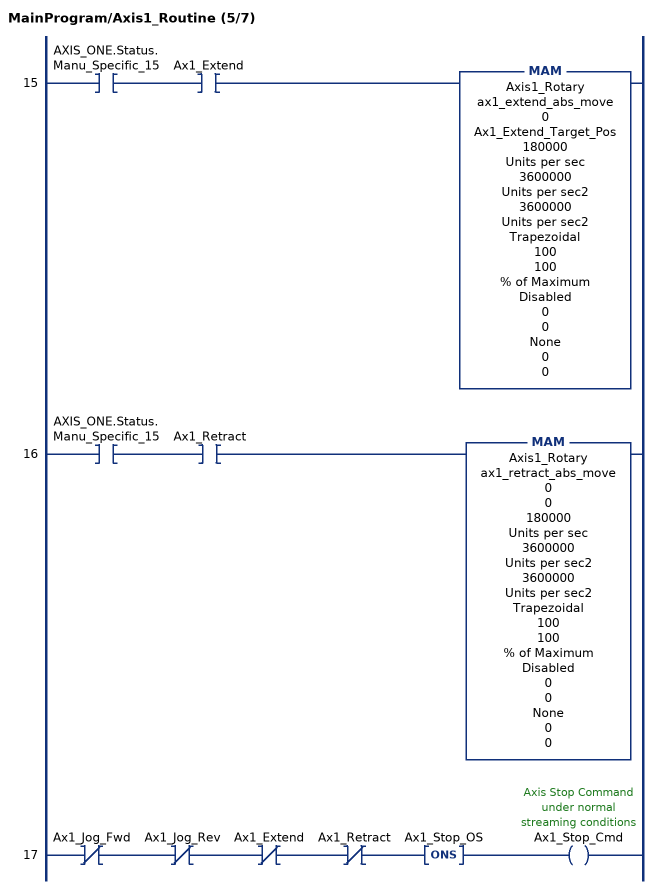
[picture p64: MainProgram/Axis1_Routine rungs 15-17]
   15: XIC(AXIS_ONE.Status.Manu_Specific_15)XIC(Ax1_Extend)MAM(Axis1_Rotary,ax1_extend_abs_move,0,Ax1_Extend_Target_Pos,180000,Units per sec,3600000,Units per sec2,3600000,Units per sec2,Trapezoidal,100,100,% of Maximum,Disabled,0,0,None,0,0);
   16: XIC(AXIS_ONE.Status.Manu_Specific_15)XIC(Ax1_Retract)MAM(Axis1_Rotary,ax1_retract_abs_move,0,0,180000,Units per sec,3600000,Units per sec2,3600000,Units per sec2,Trapezoidal,100,100,% of Maximum,Disabled,0,0,None,0,0);
   17: XIO(Ax1_Jog_Fwd)XIO(Ax1_Jog_Rev)XIO(Ax1_Extend)XIO(Ax1_Retract)ONS(Ax1_Stop_OS)OTE(Ax1_Stop_Cmd);
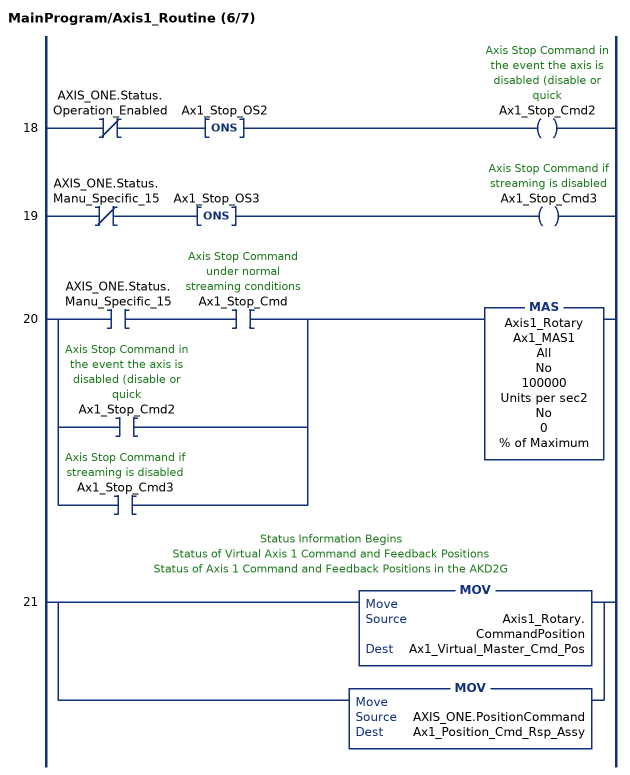
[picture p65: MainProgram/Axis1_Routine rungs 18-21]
   18: XIO(AXIS_ONE.Status.Operation_Enabled)ONS(Ax1_Stop_OS2)OTE(Ax1_Stop_Cmd2);
   19: XIO(AXIS_ONE.Status.Manu_Specific_15)ONS(Ax1_Stop_OS3)OTE(Ax1_Stop_Cmd3);
   20: [XIC(AXIS_ONE.Status.Manu_Specific_15) XIC(Ax1_Stop_Cmd) ,XIC(Ax1_Stop_Cmd2) ,XIC(Ax1_Stop_Cmd3) ]MAS(Axis1_Rotary,Ax1_MAS1,All,No,100000,Units per sec2,No,0,% of Maximum);
   // Status Information Begins
   // Status of Virtual Axis 1 Command and Feedback Positions
   // Status of Axis 1 Command and Feedback Positions in the AKD2G
   21: [MOV(Axis1_Rotary.CommandPosition,Ax1_Virtual_Master_Cmd_Pos) ,MOV(AXIS_ONE.PositionCommand,Ax1_Position_Cmd_Rsp_Assy) ];
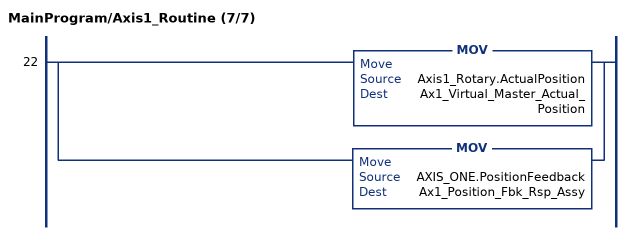
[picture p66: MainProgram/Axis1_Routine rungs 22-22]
   22: [MOV(Axis1_Rotary.ActualPosition,Ax1_Virtual_Master_Actual_Position) ,MOV(AXIS_ONE.PositionFeedback,Ax1_Position_Fbk_Rsp_Assy) ];
END_ROUTINE

ROUTINE Axis2_Routine   (* ladder *)
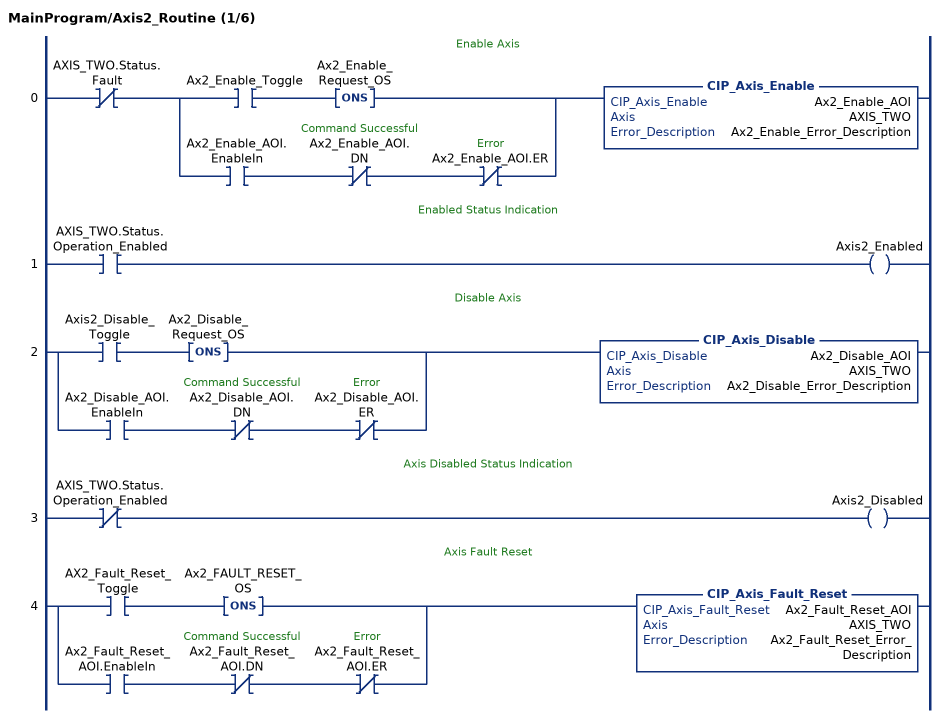
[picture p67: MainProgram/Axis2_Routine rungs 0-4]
   // Enable Axis
   0: XIO(AXIS_TWO.Status.Fault)[XIC(Ax2_Enable_Toggle) ONS(Ax2_Enable_Request_OS) ,XIC(Ax2_Enable_AOI.EnableIn) XIO(Ax2_Enable_AOI.DN) XIO(Ax2_Enable_AOI.ER) ]CIP_Axis_Enable(Ax2_Enable_AOI,AXIS_TWO,Ax2_Enable_Error_Description);
   // Enabled Status Indication
   1: XIC(AXIS_TWO.Status.Operation_Enabled)OTE(Axis2_Enabled);
   // Disable Axis
   2: [XIC(Axis2_Disable_Toggle) ONS(Ax2_Disable_Request_OS) ,XIC(Ax2_Disable_AOI.EnableIn) XIO(Ax2_Disable_AOI.DN) XIO(Ax2_Disable_AOI.ER) ]CIP_Axis_Disable(Ax2_Disable_AOI,AXIS_TWO,Ax2_Disable_Error_Description);
   // Axis Disabled Status Indication
   3: XIO(AXIS_TWO.Status.Operation_Enabled)OTE(Axis2_Disabled);
   // Axis Fault Reset
   4: [XIC(AX2_Fault_Reset_Toggle) ONS(Ax2_FAULT_RESET_OS) ,XIC(Ax2_Fault_Reset_AOI.EnableIn) XIO(Ax2_Fault_Reset_AOI.DN) XIO(Ax2_Fault_Reset_AOI.ER) ]CIP_Axis_Fault_Reset(Ax2_Fault_Reset_AOI,AXIS_TWO,Ax2_Fault_Reset_Error_Description);
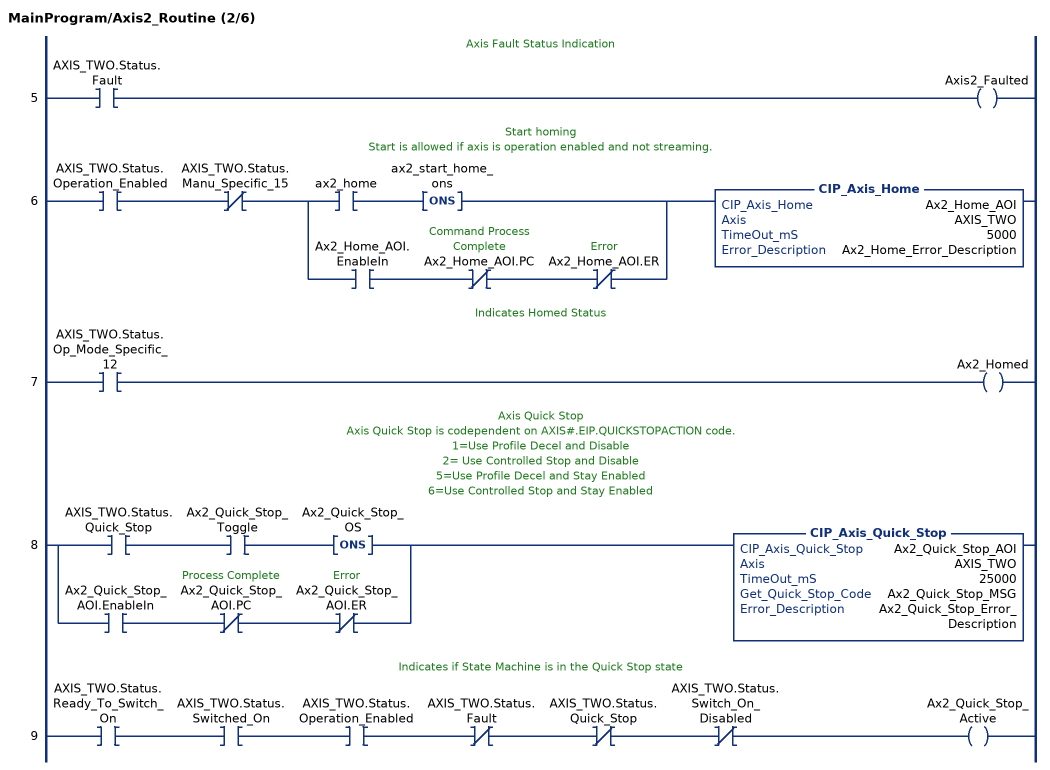
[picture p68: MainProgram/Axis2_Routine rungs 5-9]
   // Axis Fault Status Indication
   5: XIC(AXIS_TWO.Status.Fault)OTE(Axis2_Faulted);
   // Start homing
   // Start is allowed if axis is operation enabled and not streaming.
   6: XIC(AXIS_TWO.Status.Operation_Enabled)XIO(AXIS_TWO.Status.Manu_Specific_15)[XIC(ax2_home) ONS(ax2_start_home_ons) ,XIC(Ax2_Home_AOI.EnableIn) XIO(Ax2_Home_AOI.PC) XIO(Ax2_Home_AOI.ER) ]CIP_Axis_Home(Ax2_Home_AOI,AXIS_TWO,5000,Ax2_Home_Error_Description);
   // Indicates Homed Status
   7: XIC(AXIS_TWO.Status.Op_Mode_Specific_12)OTE(Ax2_Homed);
   // Axis Quick Stop
   // Axis Quick Stop is codependent on AXIS#.EIP.QUICKSTOPACTION code.
   // 1=Use Profile Decel and Disable
   // 2= Use Controlled Stop and Disable
   // 5=Use Profile Decel and Stay Enabled
   // 6=Use Controlled Stop and Stay Enabled
   8: [XIC(AXIS_TWO.Status.Quick_Stop) XIC(Ax2_Quick_Stop_Toggle) ONS(Ax2_Quick_Stop_OS) ,XIC(Ax2_Quick_Stop_AOI.EnableIn) XIO(Ax2_Quick_Stop_AOI.PC) XIO(Ax2_Quick_Stop_AOI.ER) ]CIP_Axis_Quick_Stop(Ax2_Quick_Stop_AOI,AXIS_TWO,25000,Ax2_Quick_Stop_MSG,Ax2_Quick_Stop_Error_Description);
   // Indicates if State Machine is in the Quick Stop state
   9: XIC(AXIS_TWO.Status.Ready_To_Switch_On)XIC(AXIS_TWO.Status.Switched_On)XIC(AXIS_TWO.Status.Operation_Enabled)XIO(AXIS_TWO.Status.Fault)XIO(AXIS_TWO.Status.Quick_Stop)XIO(AXIS_TWO.Status.Switch_On_Disabled)OTE(Ax2_Quick_Stop_Active);
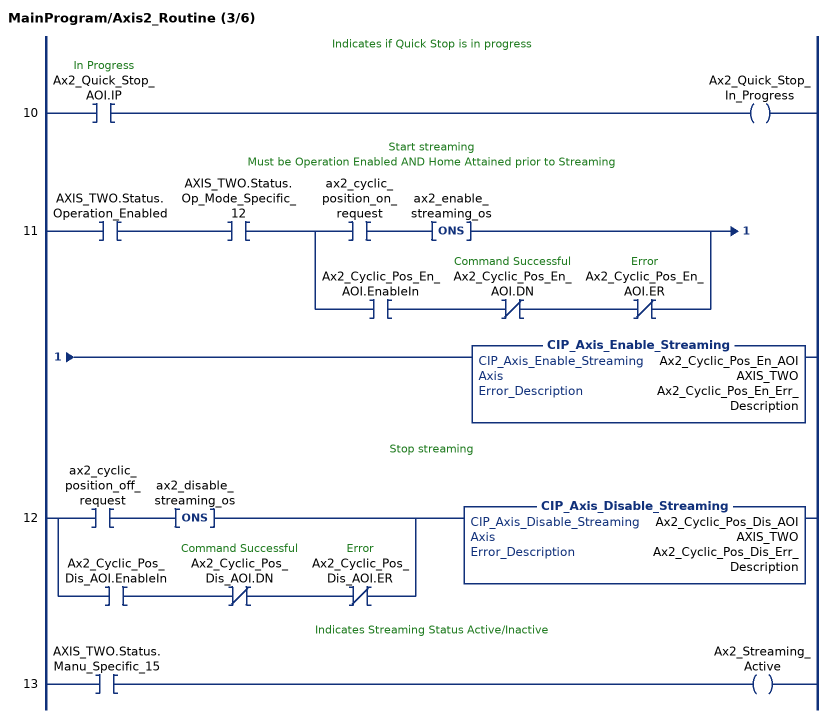
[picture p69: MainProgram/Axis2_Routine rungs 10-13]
   // Indicates if Quick Stop is in progress
   10: XIC(Ax2_Quick_Stop_AOI.IP)OTE(Ax2_Quick_Stop_In_Progress);
   // Start streaming
   // Must be Operation Enabled AND Home Attained prior to Streaming
   11: XIC(AXIS_TWO.Status.Operation_Enabled)XIC(AXIS_TWO.Status.Op_Mode_Specific_12)[XIC(ax2_cyclic_position_on_request) ONS(ax2_enable_streaming_os) ,XIC(Ax2_Cyclic_Pos_En_AOI.EnableIn) XIO(Ax2_Cyclic_Pos_En_AOI.DN) XIO(Ax2_Cyclic_Pos_En_AOI.ER) ]CIP_Axis_Enable_Streaming(Ax2_Cyclic_Pos_En_AOI,AXIS_TWO,Ax2_Cyclic_Pos_En_Err_Description);
   // Stop streaming
   12: [XIC(ax2_cyclic_position_off_request) ONS(ax2_disable_streaming_os) ,XIC(Ax2_Cyclic_Pos_Dis_AOI.EnableIn) XIO(Ax2_Cyclic_Pos_Dis_AOI.DN) XIO(Ax2_Cyclic_Pos_Dis_AOI.ER) ]CIP_Axis_Disable_Streaming(Ax2_Cyclic_Pos_Dis_AOI,AXIS_TWO,Ax2_Cyclic_Pos_Dis_Err_Description);
   // Indicates Streaming Status Active/Inactive
   13: XIC(AXIS_TWO.Status.Manu_Specific_15)OTE(Ax2_Streaming_Active);
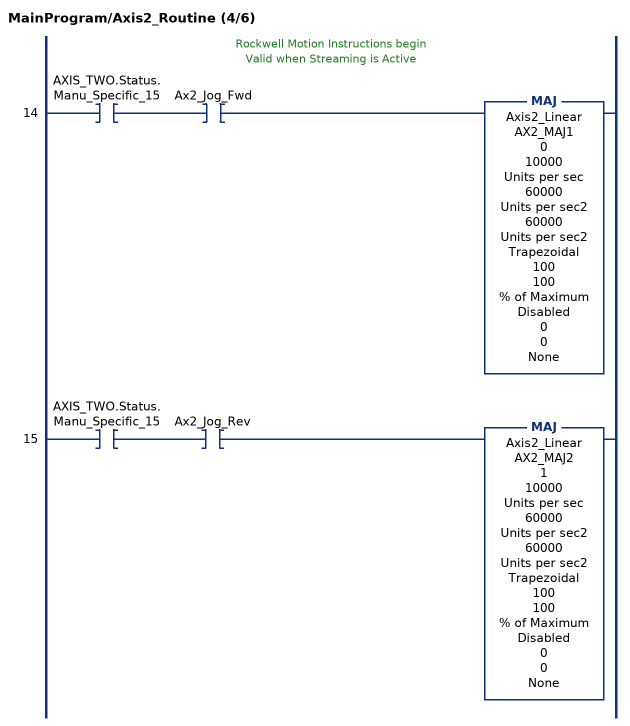
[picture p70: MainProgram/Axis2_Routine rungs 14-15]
   // Rockwell Motion Instructions begin
   // Valid when Streaming is Active
   14: XIC(AXIS_TWO.Status.Manu_Specific_15)XIC(Ax2_Jog_Fwd)MAJ(Axis2_Linear,AX2_MAJ1,0,10000,Units per sec,60000,Units per sec2,60000,Units per sec2,Trapezoidal,100,100,% of Maximum,Disabled,0,0,None);
   15: XIC(AXIS_TWO.Status.Manu_Specific_15)XIC(Ax2_Jog_Rev)MAJ(Axis2_Linear,AX2_MAJ2,1,10000,Units per sec,60000,Units per sec2,60000,Units per sec2,Trapezoidal,100,100,% of Maximum,Disabled,0,0,None);
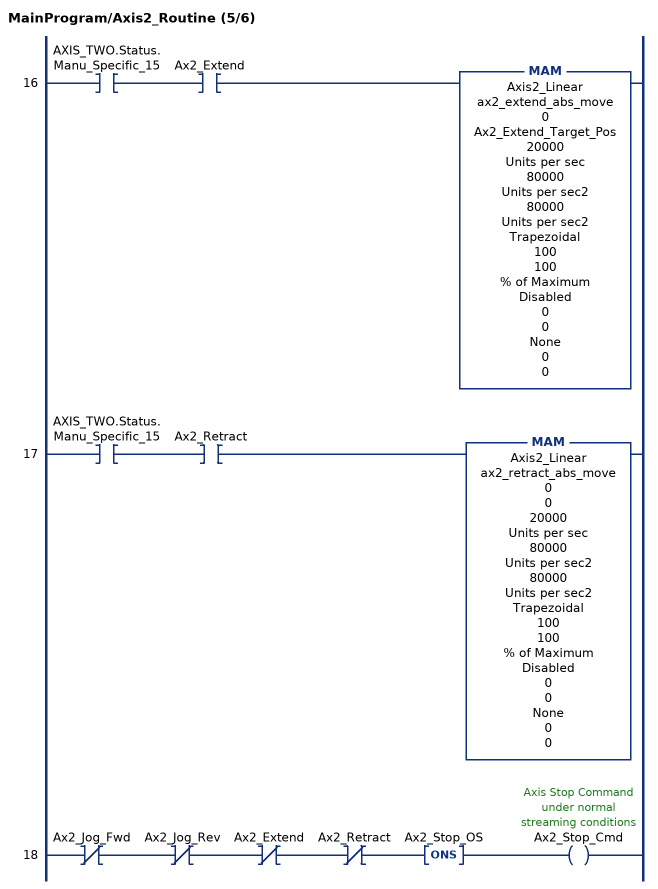
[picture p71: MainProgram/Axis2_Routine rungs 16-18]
   16: XIC(AXIS_TWO.Status.Manu_Specific_15)XIC(Ax2_Extend)MAM(Axis2_Linear,ax2_extend_abs_move,0,Ax2_Extend_Target_Pos,20000,Units per sec,80000,Units per sec2,80000,Units per sec2,Trapezoidal,100,100,% of Maximum,Disabled,0,0,None,0,0);
   17: XIC(AXIS_TWO.Status.Manu_Specific_15)XIC(Ax2_Retract)MAM(Axis2_Linear,ax2_retract_abs_move,0,0,20000,Units per sec,80000,Units per sec2,80000,Units per sec2,Trapezoidal,100,100,% of Maximum,Disabled,0,0,None,0,0);
   18: XIO(Ax2_Jog_Fwd)XIO(Ax2_Jog_Rev)XIO(Ax2_Extend)XIO(Ax2_Retract)ONS(Ax2_Stop_OS)OTE(Ax2_Stop_Cmd);
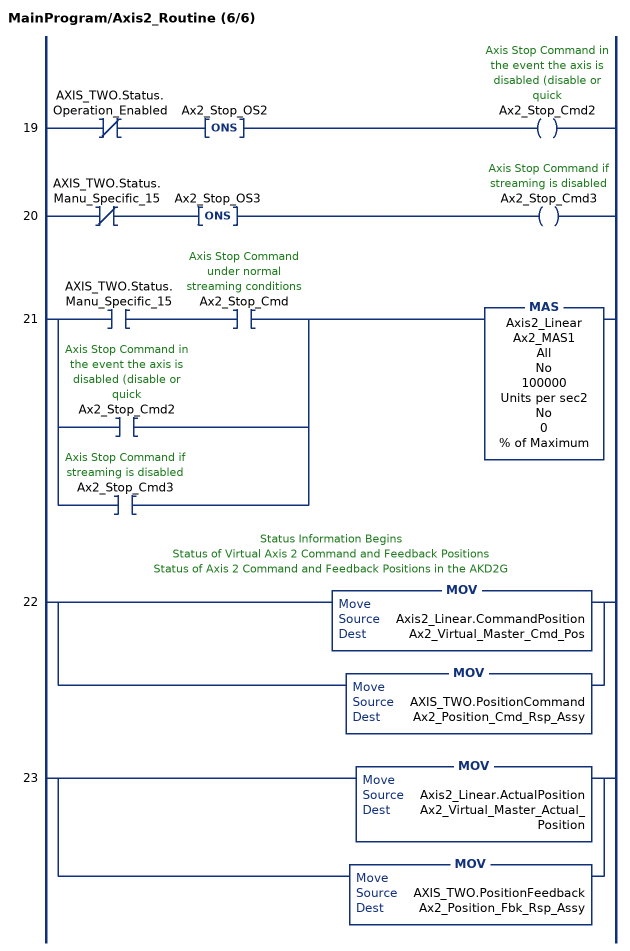
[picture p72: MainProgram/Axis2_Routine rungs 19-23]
   19: XIO(AXIS_TWO.Status.Operation_Enabled)ONS(Ax2_Stop_OS2)OTE(Ax2_Stop_Cmd2);
   20: XIO(AXIS_TWO.Status.Manu_Specific_15)ONS(Ax2_Stop_OS3)OTE(Ax2_Stop_Cmd3);
   21: [XIC(AXIS_TWO.Status.Manu_Specific_15) XIC(Ax2_Stop_Cmd) ,XIC(Ax2_Stop_Cmd2) ,XIC(Ax2_Stop_Cmd3) ]MAS(Axis2_Linear,Ax2_MAS1,All,No,100000,Units per sec2,No,0,% of Maximum);
   // Status Information Begins
   // Status of Virtual Axis 2 Command and Feedback Positions
   // Status of Axis 2 Command and Feedback Positions in the AKD2G
   22: [MOV(Axis2_Linear.CommandPosition,Ax2_Virtual_Master_Cmd_Pos) ,MOV(AXIS_TWO.PositionCommand,Ax2_Position_Cmd_Rsp_Assy) ];
   23: [MOV(Axis2_Linear.ActualPosition,Ax2_Virtual_Master_Actual_Position) ,MOV(AXIS_TWO.PositionFeedback,Ax2_Position_Fbk_Rsp_Assy) ];
END_ROUTINE

ROUTINE MainRoutine_with_CIP_State_Machines   (* ladder *)
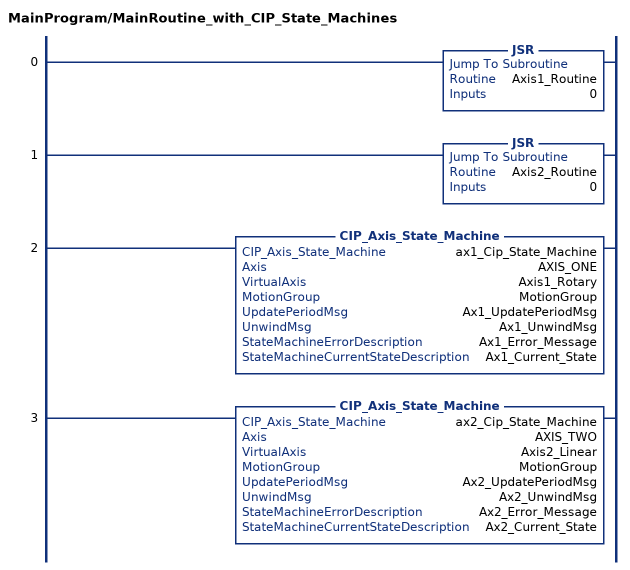
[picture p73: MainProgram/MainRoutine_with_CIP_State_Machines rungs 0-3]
   0: JSR(Axis1_Routine,0);
   1: JSR(Axis2_Routine,0);
   2: CIP_Axis_State_Machine(ax1_Cip_State_Machine,AXIS_ONE,Axis1_Rotary,MotionGroup,Ax1_UpdatePeriodMsg,Ax1_UnwindMsg,Ax1_Error_Message,Ax1_Current_State);
   3: CIP_Axis_State_Machine(ax2_Cip_State_Machine,AXIS_TWO,Axis2_Linear,MotionGroup,Ax2_UpdatePeriodMsg,Ax2_UnwindMsg,Ax2_Error_Message,Ax2_Current_State);
END_ROUTINE
END_PROGRAM
